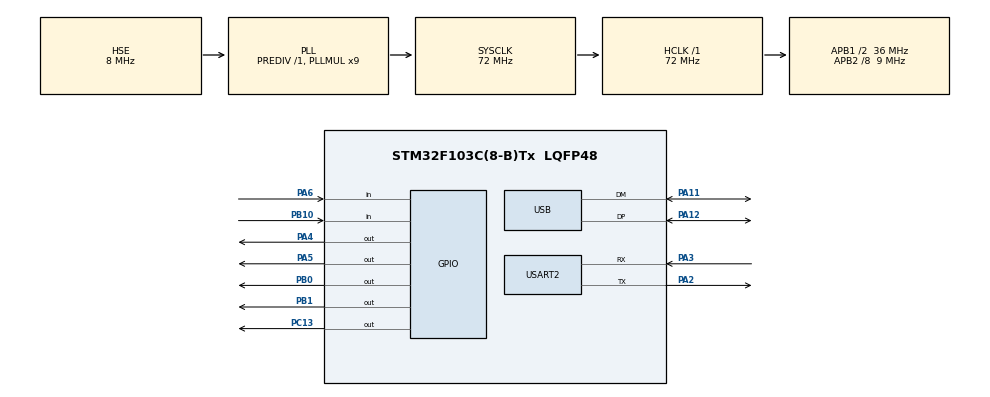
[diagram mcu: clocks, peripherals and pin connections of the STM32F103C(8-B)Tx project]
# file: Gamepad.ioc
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Mcu.Family=STM32F1
Mcu.Name=STM32F103C(8-B)Tx
Mcu.Package=LQFP48
NVIC.PriorityGroup=NVIC_PRIORITYGROUP_4
NVIC.TIM2_IRQn=true\:0\:0\:false\:false\:true\:true\:true
NVIC.USART2_IRQn=true\:0\:0\:false\:false\:true\:true\:true
NVIC.USB_LP_CAN1_RX0_IRQn=true\:0\:0\:false\:false\:true\:false\:true
PA11.Mode=Device
PA11.Signal=USB_DM
PA12.Mode=Device
PA12.Signal=USB_DP
PA13.Mode=Serial_Wire
PA13.Signal=SYS_JTMS-SWDIO
PA14.Mode=Serial_Wire
PA14.Signal=SYS_JTCK-SWCLK
PA2.Mode=Asynchronous
PA2.Signal=USART2_TX
PA3.Mode=Asynchronous
PA3.Signal=USART2_RX
PA4.GPIO_Speed=GPIO_SPEED_FREQ_HIGH
PA4.PinState=GPIO_PIN_RESET
PA4.Signal=GPIO_Output
PA5.GPIO_Speed=GPIO_SPEED_FREQ_HIGH
PA5.PinState=GPIO_PIN_RESET
PA5.Signal=GPIO_Output
PA6.GPIO_PuPd=GPIO_PULLUP
PA6.Signal=GPIO_Input
PB0.GPIO_Speed=GPIO_SPEED_FREQ_HIGH
PB0.Signal=GPIO_Output
PB1.GPIO_Speed=GPIO_SPEED_FREQ_HIGH
PB1.Signal=GPIO_Output
PB10.GPIO_PuPd=GPIO_PULLUP
PB10.Signal=GPIO_Input
PC13-TAMPER-RTC.GPIO_Speed=GPIO_SPEED_FREQ_HIGH
PC13-TAMPER-RTC.Signal=GPIO_Output
PD0-OSC_IN.Mode=HSE-External-Oscillator
PD0-OSC_IN.Signal=RCC_OSC_IN
PD1-OSC_OUT.Mode=HSE-External-Oscillator
PD1-OSC_OUT.Signal=RCC_OSC_OUT
ProjectManager.HeapSize=0x200
ProjectManager.StackSize=0x400
ProjectManager.TargetToolchain=MDK-ARM V5
RCC.AHBFreq_Value=72000000
RCC.APB1CLKDivider=RCC_HCLK_DIV2
RCC.APB1Freq_Value=36000000
RCC.APB1TimFreq_Value=72000000
RCC.APB2CLKDivider=RCC_HCLK_DIV8
RCC.APB2Freq_Value=9000000
RCC.APB2TimFreq_Value=18000000
RCC.HCLKFreq_Value=72000000
RCC.PLLMUL=RCC_PLL_MUL9
RCC.SYSCLKFreq_VALUE=72000000
RCC.SYSCLKSource=RCC_SYSCLKSOURCE_PLLCLK
RCC.USBFreq_Value=48000000
RCC.USBPrescaler=RCC_USBCLKSOURCE_PLL_DIV1_5
TIM2.Period=16*2
TIM2.Prescaler=35999
TIM2.TIM_MasterSlaveMode=TIM_MASTERSLAVEMODE_DISABLE
USART2.VirtualMode=VM_ASYNC
USB_DEVICE.CLASS_NAME_FS=CUSTOM_HID
USB_DEVICE.VirtualMode=CustomHid
USB_DEVICE.VirtualModeFS=Custom_Hid_FS
VP_TIM2_VS_ClockSourceINT.Mode=Internal
VP_USB_DEVICE_VS_USB_DEVICE_CUSTOM_HID_FS.Mode=CUSTOM_HID_FS
board=custom

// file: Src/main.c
/* USER CODE BEGIN Header */
/**
  ******************************************************************************
  * @file           : main.c
  * @brief          : Main program body
  ******************************************************************************
  * @attention
  *
  * <h2><center>&copy; Copyright (c) 2019 STMicroelectronics.
  * All rights reserved.</center></h2>
  *
  * This software component is licensed by ST under Ultimate Liberty license
  * SLA0044, the "License"; You may not use this file except in compliance with
  * the License. You may obtain a copy of the License at:
  *                             www.st.com/SLA0044
  *
  ******************************************************************************
  */
/* USER CODE END Header */

#include "main.h"
#include "usb_device.h"

/* USER CODE BEGIN Includes */
#include "usbd_custom_hid_if.h"
#include "dwt.h"
#include "read_joy.h"

/* USER CODE END Includes */

/* USER CODE BEGIN PD */

//#define _DEBUG
volatile uint8_t m_gamepad_updated = 0;
volatile uint8_t m_usb_report_need_update = 0;

/* USER CODE END PD */

UART_HandleTypeDef huart2;

/* USER CODE BEGIN PV */
TIM_HandleTypeDef htim2_gamepad;

extern USBD_HandleTypeDef hUsbDeviceFS;

volatile uint8_t byte1 = 0;
volatile uint8_t byte2 = 0;
volatile uint8_t rep[16] = {0};

void HAL_TIM_PeriodElapsedCallback(TIM_HandleTypeDef *htim)
{
    if(htim->Instance == TIM2) {
        m_gamepad_updated = 1;
    }
}

/* USER CODE END PV */

void SystemClock_Config(void);
static void MX_GPIO_Init(void);
static void MX_USART2_UART_Init(void);
static void MX_TIM2_Init(void);

int main(void)
{

  /* MCU Configuration--------------------------------------------------------*/

  /* Reset of all peripherals, Initializes the Flash interface and the Systick. */
  HAL_Init();

  /* Configure the system clock */
  SystemClock_Config();

  /* Initialize all configured peripherals */
  MX_GPIO_Init();
  MX_USB_DEVICE_Init();
  MX_USART2_UART_Init();
  MX_TIM2_Init();
  /* USER CODE BEGIN 2 */

  HAL_TIM_Base_Start_IT(&htim2_gamepad);
  /* USER CODE END 2 */

  /* Infinite loop */
  /* USER CODE BEGIN WHILE */

    if (__HAL_RCC_GET_FLAG(RCC_FLAG_IWDGRST)) {
            HAL_UART_Transmit(&huart2, (uint8_t *)"reset\r\n", 7, 50);
    } else {
            HAL_UART_Transmit(&huart2, (uint8_t *)"init\r\n", 6, 50);
    }

    // keyboard codes 0-9
//    uint8_t button_code[10] = {
//        0x27,         // 0
//        0x1E,         // 1
//        0x1F,         // 2
//        0x20,         // 3
//        0x21,         // 4
//        0x22,         // 5
//        0x23,         // 6
//        0x24,         // 7
//        0x25,         // 8
//        0x26          // 9
//    };
//    uint8_t button_code[10] = {
//        0x10,         // 0
//        0x11,         // 1
//        0x12,         // 2
//        0x13,         // 3
//        0x14,         // 4
//        0x15,         // 5
//        0x16,         // 6
//        0x17,         // 7
//        0x18,         // 8
//        0x19          // 9
//    };

  Joy_Control joys;
  InitControl_Joysticks(&joys);
  joys.init();

  while (1)
  {

#ifdef _DEBUG
        static uint8_t one = 1;
        if (byte1 != 0xFF || byte2 != 0xFF) {
            char tmp[64];
            if (one) {
                one = 0;
                sprintf(tmp, "first gamepad data: %02X:%s:%s:%s:%s:%s:%s:%s:%s\r\n", byte1
                , !((byte1 >> 7) & 1) ? "RIGHT" : ""
                , !((byte1 >> 6) & 1) ? "LEFT" : ""
                , !((byte1 >> 5) & 1) ? "DOWN" : ""
                , !((byte1 >> 4) & 1) ? "UP" : ""
                , !((byte1 >> 3) & 1) ? "START" : ""
                , !((byte1 >> 2) & 1) ? "SELECT" : ""
                , !((byte1 >> 1) & 1) ? "B" : ""
                , !((byte1 >> 0) & 1) ? "A" : "");
                HAL_UART_Transmit(&huart2, (uint8_t *)tmp, strlen(tmp), 50);
                sprintf(tmp, "second gamepad data: %02X:%s:%s:%s:%s:%s:%s:%s:%s\r\n", byte2
                , !((byte2 >> 7) & 1) ? "RIGHT" : ""
                , !((byte2 >> 6) & 1) ? "LEFT" : ""
                , !((byte2 >> 5) & 1) ? "DOWN" : ""
                , !((byte2 >> 4) & 1) ? "UP" : ""
                , !((byte2 >> 3) & 1) ? "START" : ""
                , !((byte2 >> 2) & 1) ? "SELECT" : ""
                , !((byte2 >> 1) & 1) ? "B" : ""
                , !((byte2 >> 0) & 1) ? "A" : "");
                HAL_UART_Transmit(&huart2, (uint8_t *)tmp, strlen(tmp), 50);
            }
        } else {
            one = 1;
        }
#endif

    if (m_gamepad_updated) {
        m_gamepad_updated = 0;

        joys.read_joys();
        joys.send_report();
    }

    /* USER CODE END WHILE */

  }
}

void SystemClock_Config(void)
{
  RCC_OscInitTypeDef RCC_OscInitStruct = {0};
  RCC_ClkInitTypeDef RCC_ClkInitStruct = {0};
  RCC_PeriphCLKInitTypeDef PeriphClkInit = {0};

  /** Initializes the CPU, AHB and APB busses clocks
  */
  RCC_OscInitStruct.OscillatorType = RCC_OSCILLATORTYPE_HSE;
  RCC_OscInitStruct.HSEState = RCC_HSE_ON;
  RCC_OscInitStruct.HSEPredivValue = RCC_HSE_PREDIV_DIV1;
  RCC_OscInitStruct.HSIState = RCC_HSI_ON;
  RCC_OscInitStruct.PLL.PLLState = RCC_PLL_ON;
  RCC_OscInitStruct.PLL.PLLSource = RCC_PLLSOURCE_HSE;
  RCC_OscInitStruct.PLL.PLLMUL = RCC_PLL_MUL9;
  if (HAL_RCC_OscConfig(&RCC_OscInitStruct) != HAL_OK)
  {
    Error_Handler();
  }
  /** Initializes the CPU, AHB and APB busses clocks
  */
  RCC_ClkInitStruct.ClockType = RCC_CLOCKTYPE_HCLK|RCC_CLOCKTYPE_SYSCLK
                              |RCC_CLOCKTYPE_PCLK1|RCC_CLOCKTYPE_PCLK2;
  RCC_ClkInitStruct.SYSCLKSource = RCC_SYSCLKSOURCE_PLLCLK;
  RCC_ClkInitStruct.AHBCLKDivider = RCC_SYSCLK_DIV1;
  RCC_ClkInitStruct.APB1CLKDivider = RCC_HCLK_DIV2;
  RCC_ClkInitStruct.APB2CLKDivider = RCC_HCLK_DIV8;

  if (HAL_RCC_ClockConfig(&RCC_ClkInitStruct, FLASH_LATENCY_2) != HAL_OK)
  {
    Error_Handler();
  }
  PeriphClkInit.PeriphClockSelection = RCC_PERIPHCLK_USB;
  PeriphClkInit.UsbClockSelection = RCC_USBCLKSOURCE_PLL_DIV1_5;
  if (HAL_RCCEx_PeriphCLKConfig(&PeriphClkInit) != HAL_OK)
  {
    Error_Handler();
  }
}

static void MX_TIM2_Init(void)
{

  TIM_ClockConfigTypeDef sClockSourceConfig = {0};
  TIM_MasterConfigTypeDef sMasterConfig = {0};

  htim2_gamepad.Instance = TIM2;
  htim2_gamepad.Init.Prescaler = 35999 - 2;
  htim2_gamepad.Init.CounterMode = TIM_COUNTERMODE_UP;
  htim2_gamepad.Init.Period = 16 * 2 - 1;
  htim2_gamepad.Init.ClockDivision = TIM_CLOCKDIVISION_DIV1;
  htim2_gamepad.Init.AutoReloadPreload = TIM_AUTORELOAD_PRELOAD_DISABLE;
  if (HAL_TIM_Base_Init(&htim2_gamepad) != HAL_OK)
  {
    Error_Handler();
  }
  sClockSourceConfig.ClockSource = TIM_CLOCKSOURCE_INTERNAL;
  if (HAL_TIM_ConfigClockSource(&htim2_gamepad, &sClockSourceConfig) != HAL_OK)
  {
    Error_Handler();
  }
  sMasterConfig.MasterOutputTrigger = TIM_TRGO_RESET;
  sMasterConfig.MasterSlaveMode = TIM_MASTERSLAVEMODE_DISABLE;
  if (HAL_TIMEx_MasterConfigSynchronization(&htim2_gamepad, &sMasterConfig) != HAL_OK)
  {
    Error_Handler();
  }

}

static void MX_USART2_UART_Init(void)
{

  huart2.Instance = USART2;
  huart2.Init.BaudRate = 115200;
  huart2.Init.WordLength = UART_WORDLENGTH_8B;
  huart2.Init.StopBits = UART_STOPBITS_1;
  huart2.Init.Parity = UART_PARITY_NONE;
  huart2.Init.Mode = UART_MODE_TX_RX;
  huart2.Init.HwFlowCtl = UART_HWCONTROL_NONE;
  huart2.Init.OverSampling = UART_OVERSAMPLING_16;
  if (HAL_UART_Init(&huart2) != HAL_OK)
  {
    Error_Handler();
  }

}

static void MX_GPIO_Init(void)
{
  GPIO_InitTypeDef GPIO_InitStruct = {0};

  /* GPIO Ports Clock Enable */
  __HAL_RCC_GPIOC_CLK_ENABLE();
  __HAL_RCC_GPIOD_CLK_ENABLE();
  __HAL_RCC_GPIOA_CLK_ENABLE();
  __HAL_RCC_GPIOB_CLK_ENABLE();

  /*Configure GPIO pin Output Level */
  HAL_GPIO_WritePin(GPIOC, GPIO_PIN_13, GPIO_PIN_RESET);

  /*Configure GPIO pin Output Level */
  HAL_GPIO_WritePin(GPIOA, GPIO_PIN_4|GPIO_PIN_5|GPIO_PIN_10|GPIO_PIN_0, GPIO_PIN_RESET);

  /*Configure GPIO pin Output Level */
  HAL_GPIO_WritePin(GPIOB, GPIO_PIN_0|GPIO_PIN_1|GPIO_PIN_6, GPIO_PIN_RESET);

  /*Configure GPIO pin : PC13 */
  GPIO_InitStruct.Pin = GPIO_PIN_13;
  GPIO_InitStruct.Mode = GPIO_MODE_OUTPUT_PP;
  GPIO_InitStruct.Pull = GPIO_PULLUP;
  GPIO_InitStruct.Speed = GPIO_SPEED_FREQ_HIGH;
  HAL_GPIO_Init(GPIOC, &GPIO_InitStruct);

  /*Configure GPIO pins : PA4 PA5 PA10 PA0*/
  GPIO_InitStruct.Pin = GPIO_PIN_4|GPIO_PIN_5|GPIO_PIN_10|GPIO_PIN_0;
  GPIO_InitStruct.Mode = GPIO_MODE_OUTPUT_PP;
  GPIO_InitStruct.Pull = GPIO_PULLUP;
  GPIO_InitStruct.Speed = GPIO_SPEED_FREQ_HIGH;
  HAL_GPIO_Init(GPIOA, &GPIO_InitStruct);

  /*Configure GPIO pin : PA6 PA8 PA9 PA15*/
  GPIO_InitStruct.Pin = GPIO_PIN_6|GPIO_PIN_8|GPIO_PIN_9|GPIO_PIN_15;
  GPIO_InitStruct.Mode = GPIO_MODE_INPUT;
  GPIO_InitStruct.Pull = GPIO_PULLUP;
  HAL_GPIO_Init(GPIOA, &GPIO_InitStruct);

  /*Configure GPIO pins : PB0 PB1 PB6*/
  GPIO_InitStruct.Pin = GPIO_PIN_0|GPIO_PIN_1|GPIO_PIN_6;
  GPIO_InitStruct.Mode = GPIO_MODE_OUTPUT_PP;
  GPIO_InitStruct.Pull = GPIO_PULLUP;
  GPIO_InitStruct.Speed = GPIO_SPEED_FREQ_HIGH;
  HAL_GPIO_Init(GPIOB, &GPIO_InitStruct);

  /*Configure GPIO pin : PB10 PB12-PB15 PB3 PB4 PB5*/
  GPIO_InitStruct.Pin = GPIO_PIN_10|GPIO_PIN_12|GPIO_PIN_13|GPIO_PIN_14|GPIO_PIN_15|GPIO_PIN_3|GPIO_PIN_4|GPIO_PIN_5|GPIO_PIN_7|GPIO_PIN_8;
  GPIO_InitStruct.Mode = GPIO_MODE_INPUT;
  GPIO_InitStruct.Pull = GPIO_PULLUP;
  HAL_GPIO_Init(GPIOB, &GPIO_InitStruct);

}

void Error_Handler(void)
{
}

/************************ (C) COPYRIGHT STMicroelectronics *****END OF FILE****/
